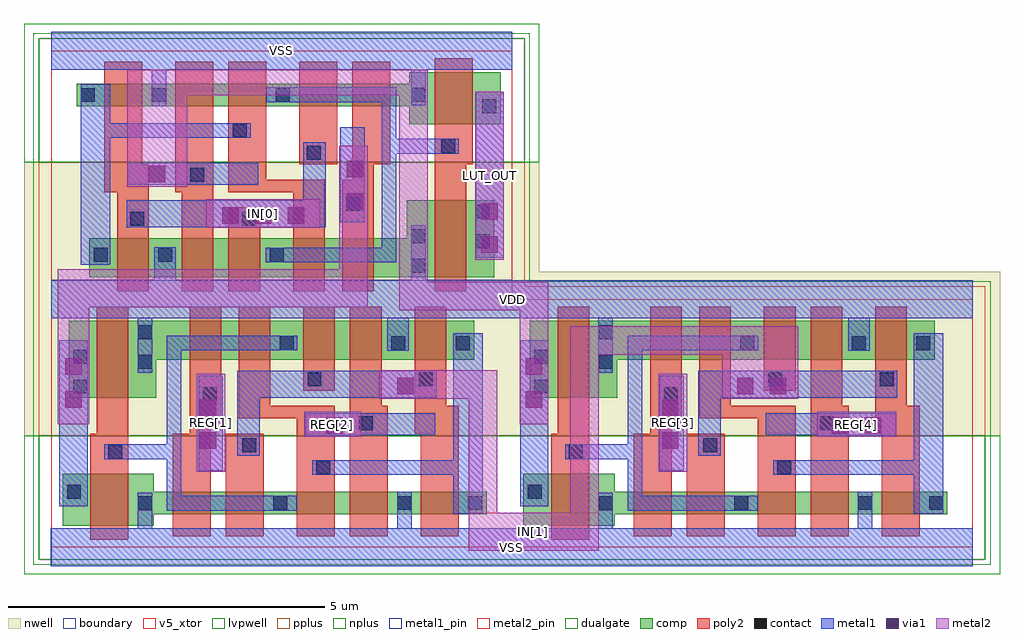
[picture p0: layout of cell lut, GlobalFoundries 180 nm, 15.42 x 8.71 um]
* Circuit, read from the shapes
.subckt lut IN[0] IN[1] LUT_OUT REG[1] REG[2] REG[3] REG[4] VDD VSS
XM1 VSS n1 gf180mcu_fd_sc_mcu7t5v0__mux2_1_2/I1 VSUBS nfet_05v0 w=0.82u l=0.6u
XM2 VSS IN[0] n2 VSUBS nfet_05v0 w=0.36u l=0.6u
XM3 n3 REG[1] VSS VSUBS nfet_05v0 w=0.36u l=0.6u
XM4 n4 gf180mcu_fd_sc_mcu7t5v0__mux2_1_2/I0 VSS VSUBS nfet_05v0 w=0.36u l=0.6u
XM5 n1 IN[1] n3 VSUBS nfet_05v0 w=0.36u l=0.6u
XM6 n5 n2 n4 VSUBS nfet_05v0 w=0.36u l=0.6u
XM7 n6 n7 n1 VSUBS nfet_05v0 w=0.36u l=0.6u
XM8 n8 IN[0] n5 VSUBS nfet_05v0 w=0.36u l=0.6u
XM9 VSS REG[2] n6 VSUBS nfet_05v0 w=0.36u l=0.6u
XM10 VSS gf180mcu_fd_sc_mcu7t5v0__mux2_1_2/I1 n8 VSUBS nfet_05v0 w=0.36u l=0.6u
XM11 n7 IN[1] VSS VSUBS nfet_05v0 w=0.36u l=0.6u
XM12 LUT_OUT n5 VSS VSUBS nfet_05v0 w=0.82u l=0.6u
XM13 VSS n9 gf180mcu_fd_sc_mcu7t5v0__mux2_1_2/I0 VSUBS nfet_05v0 w=0.82u l=0.6u
XM14 n10 REG[3] VSS VSUBS nfet_05v0 w=0.36u l=0.6u
XM15 n9 IN[1] n10 VSUBS nfet_05v0 w=0.36u l=0.6u
XM16 n11 n12 n9 VSUBS nfet_05v0 w=0.36u l=0.6u
XM17 VSS REG[4] n11 VSUBS nfet_05v0 w=0.36u l=0.6u
XM18 n12 IN[1] VSS VSUBS nfet_05v0 w=0.36u l=0.6u
XM19 VDD n1 gf180mcu_fd_sc_mcu7t5v0__mux2_1_2/I1 gf180mcu_fd_sc_mcu7t5v0__mux2_1_0/VNW pfet_05v0 w=1.22u l=0.5u
XM20 VDD IN[0] n2 gf180mcu_fd_sc_mcu7t5v0__mux2_1_0/VNW pfet_05v0 w=0.615u l=0.5u
XM21 n13 gf180mcu_fd_sc_mcu7t5v0__mux2_1_2/I0 VDD gf180mcu_fd_sc_mcu7t5v0__mux2_1_0/VNW pfet_05v0 w=0.615u l=0.5u
XM22 n14 REG[1] VDD gf180mcu_fd_sc_mcu7t5v0__mux2_1_0/VNW pfet_05v0 w=0.615u l=0.5u
XM23 n5 IN[0] n13 gf180mcu_fd_sc_mcu7t5v0__mux2_1_0/VNW pfet_05v0 w=0.615u l=0.5u
XM24 n1 n7 n14 gf180mcu_fd_sc_mcu7t5v0__mux2_1_0/VNW pfet_05v0 w=0.615u l=0.5u
XM25 n15 n2 n5 gf180mcu_fd_sc_mcu7t5v0__mux2_1_0/VNW pfet_05v0 w=0.615u l=0.5u
XM26 n16 IN[1] n1 gf180mcu_fd_sc_mcu7t5v0__mux2_1_0/VNW pfet_05v0 w=0.615u l=0.5u
XM27 VDD gf180mcu_fd_sc_mcu7t5v0__mux2_1_2/I1 n15 gf180mcu_fd_sc_mcu7t5v0__mux2_1_0/VNW pfet_05v0 w=0.615u l=0.5u
XM28 VDD REG[2] n16 gf180mcu_fd_sc_mcu7t5v0__mux2_1_0/VNW pfet_05v0 w=0.615u l=0.5u
XM29 n7 IN[1] VDD gf180mcu_fd_sc_mcu7t5v0__mux2_1_0/VNW pfet_05v0 w=0.615u l=0.5u
XM30 LUT_OUT n5 VDD gf180mcu_fd_sc_mcu7t5v0__mux2_1_0/VNW pfet_05v0 w=1.22u l=0.5u
XM31 VDD n9 gf180mcu_fd_sc_mcu7t5v0__mux2_1_2/I0 gf180mcu_fd_sc_mcu7t5v0__mux2_1_0/VNW pfet_05v0 w=1.22u l=0.5u
XM32 n17 REG[3] VDD gf180mcu_fd_sc_mcu7t5v0__mux2_1_0/VNW pfet_05v0 w=0.615u l=0.5u
XM33 n9 n12 n17 gf180mcu_fd_sc_mcu7t5v0__mux2_1_0/VNW pfet_05v0 w=0.615u l=0.5u
XM34 n18 IN[1] n9 gf180mcu_fd_sc_mcu7t5v0__mux2_1_0/VNW pfet_05v0 w=0.615u l=0.5u
XM35 VDD REG[4] n18 gf180mcu_fd_sc_mcu7t5v0__mux2_1_0/VNW pfet_05v0 w=0.615u l=0.5u
XM36 n12 IN[1] VDD gf180mcu_fd_sc_mcu7t5v0__mux2_1_0/VNW pfet_05v0 w=0.615u l=0.5u
.ends

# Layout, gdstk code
from math import pi, radians
import gdstk
lib = gdstk.Library(unit=1e-6, precision=1e-09)
def R(c, l, rs):  # rectangles x0, y0, x1, y1
    for r in rs: c.add(gdstk.rectangle(r[:2], r[2:], *l))
def A(c, l, x, y, w, h, nx, ny, dx, dy):  # array of equal rectangles
    R(c, l, [(x+i*dx, y+j*dy, x+i*dx+w, y+j*dy+h) for i in range(nx) for j in range(ny)])
def P(c, l, *ps):  # polygons
    for p in ps: c.add(gdstk.Polygon(p, *l))
boundary = (0, 0)
nwell = (21, 0)
comp = (22, 0)
poly2 = (30, 0)
pplus = (31, 0)
nplus = (32, 0)
contact = (33, 0)
metal1 = (34, 0)
metal1_pin = (34, 10)
via1 = (35, 0)
metal2 = (36, 0)
metal2_pin = (36, 10)
dualgate = (55, 0)
v5_xtor = (112, 1)
lvpwell = (204, 0)

gf180mcu_fd_sc_mcu7t5v0_ = lib.new_cell('gf180mcu_fd_sc_mcu7t5v0__mux2_1')
R(gf180mcu_fd_sc_mcu7t5v0_, boundary, [(0,0,7.28,3.92)])
R(gf180mcu_fd_sc_mcu7t5v0_, nwell, [(-0.43,1.76,7.71,4.35)])
P(gf180mcu_fd_sc_mcu7t5v0_, comp, [(0.28,2.36),(0.28,3.58),(6.68,3.58),(6.68,2.965),(1.66,2.965),(1.66,2.36)],
  [(0.18,0.34),(0.18,1.16),(1.62,1.16),(1.62,0.88),(6.88,0.88),(6.88,0.52),(1.62,0.52),(1.62,0.34)])
R(gf180mcu_fd_sc_mcu7t5v0_, poly2, [(2.76,0.175,3.36,1.795), (3.98,2.475,4.48,3.8)])
P(gf180mcu_fd_sc_mcu7t5v0_, poly2, [(0.62,0.12),(0.62,1.795),(0.72,1.795),(0.72,3.8),(1.22,3.8),(1.22,0.12)],
  [(1.92,0.175),(1.92,1.795),(2.185,1.795),(2.185,3.8),(2.685,3.8),(2.685,2.035),(2.52,2.035),(2.52,0.175)],
  [(3.88,0.175),(3.88,2.035),(2.96,2.035),(2.96,3.8),(3.46,3.8),(3.46,2.235),(4.48,2.235),(4.48,0.175)],
  [(4.72,0.175),(4.72,3.8),(5.22,3.8),(5.22,2.235),(5.32,2.235),(5.32,0.175)],
  [(5.84,0.175),(5.84,1.795),(5.74,1.795),(5.74,3.8),(6.24,3.8),(6.24,2.235),(6.44,2.235),(6.44,0.175)])
R(gf180mcu_fd_sc_mcu7t5v0_, pplus, [(-0.2,1.76,7.48,4.12)])
R(gf180mcu_fd_sc_mcu7t5v0_, nplus, [(-0.2,-0.2,7.48,1.76)])
R(gf180mcu_fd_sc_mcu7t5v0_, contact, [(1.37,0.585,1.59,0.805), (3.51,0.59,3.73,0.81), (5.47,0.59,5.69,0.81), (6.59,0.59,6.81,0.81), (0.25,0.765,0.47,0.985), (4.19,1.15,4.41,1.37), (0.9,1.4,1.12,1.62), (3.02,1.505,3.24,1.725), (4.86,1.85,5.08,2.07), (2.395,2.305,2.615,2.525), (0.35,2.43,0.57,2.65), (4.05,2.545,4.27,2.765), (5.81,2.545,6.03,2.765), (1.37,2.82,1.59,3.04), (0.35,2.9,0.57,3.12), (3.61,3.115,3.83,3.335), (5.37,3.115,5.59,3.335), (6.39,3.115,6.61,3.335), (1.37,3.29,1.59,3.51)])
R(gf180mcu_fd_sc_mcu7t5v0_, metal1, [(0.13,0.65,0.575,3.27), (2.33,1.21,2.71,2.71), (4.01,1.77,6.07,2.12)])
P(gf180mcu_fd_sc_mcu7t5v0_, metal1, [(1.825,0.575),(1.825,1.39),(0.84,1.39),(0.84,1.625),(1.825,1.625),(1.825,3.34),(3.89,3.34),(3.89,3.11),(2.055,3.11),(2.055,0.815),(3.88,0.815),(3.88,0.575)],
  [(2.94,1.445),(2.94,2.785),(6.09,2.785),(6.09,2.36),(3.295,2.36),(3.295,1.445)],
  [(6.35,0.53),(6.35,1.145),(4.125,1.145),(4.125,1.375),(6.35,1.375),(6.35,3.38),(6.815,3.38),(6.815,0.53)],
  [(0,-0.3),(0,0.3),(1.365,0.3),(1.365,0.865),(1.595,0.865),(1.595,0.3),(5.465,0.3),(5.465,0.88),(5.695,0.88),(5.695,0.3),(7.28,0.3),(7.28,-0.3)],
  [(1.365,2.76),(1.365,3.62),(0,3.62),(0,4.22),(7.28,4.22),(7.28,3.62),(5.65,3.62),(5.65,3.105),(5.31,3.105),(5.31,3.62),(1.595,3.62),(1.595,2.76)])
R(gf180mcu_fd_sc_mcu7t5v0_, dualgate, [(-0.28,-0.28,7.56,4.2)])
R(gf180mcu_fd_sc_mcu7t5v0_, v5_xtor, [(0,0,7.28,3.92)])
R(gf180mcu_fd_sc_mcu7t5v0_, lvpwell, [(-0.43,-0.43,7.71,1.76)])
gf180mcu_fd_sc_mcu7t5v0_.add(gdstk.Label('S', (4.2,2.52), layer=34, texttype=10))
gf180mcu_fd_sc_mcu7t5v0_.add(gdstk.Label('VDD', (3.64,3.92), layer=34, texttype=10))
gf180mcu_fd_sc_mcu7t5v0_.add(gdstk.Label('VSS', (3.64,0), layer=34, texttype=10))
gf180mcu_fd_sc_mcu7t5v0_.add(gdstk.Label('Z', (0.28,1.96), layer=34, texttype=10))
gf180mcu_fd_sc_mcu7t5v0_.add(gdstk.Label('I0', (4.76,1.96), layer=34, texttype=10))
gf180mcu_fd_sc_mcu7t5v0_.add(gdstk.Label('I1', (2.52,1.96), layer=34, texttype=10))
gf180mcu_fd_sc_mcu7t5v0_.add(gdstk.Label('& Vendor GLOBALFOUNDRIES', (0,2), layer=63, texttype=63))
gf180mcu_fd_sc_mcu7t5v0_.add(gdstk.Label('& Product GF018hv5v_mcu_sc7', (0,1.5), layer=63, texttype=63))
gf180mcu_fd_sc_mcu7t5v0_.add(gdstk.Label('& Version 2015q2v1', (0,1), layer=63, texttype=63))
gf180mcu_fd_sc_mcu7t5v0_.add(gdstk.Label('& Metric 1.00', (0,0.5), layer=63, texttype=63))
gf180mcu_fd_sc_mcu7t5v0_.add(gdstk.Label('VNW', (0.345,3.92), layer=21, texttype=10))
gf180mcu_fd_sc_mcu7t5v0_.add(gdstk.Label('VPW', (0.34,-0.085), layer=204, texttype=10))

lut = lib.new_cell('lut')
R(lut, nwell, [(10.2,0.05,10.7,1.85), (5.55,0.45,5.74,0.8)])
R(lut, pplus, [(2.39,1.795,2.44,1.865), (3.4,1.795,3.905,1.865), (8.42,1.795,8.79,1.865), (2.39,1.865,8.79,2.09), (2.39,2.09,2.76,2.16), (7.275,2.09,7.78,2.16), (8.74,2.09,8.79,2.16)])
R(lut, nplus, [(8.99,-1.585,9.25,-0.905)])
R(lut, metal1, [(4.3,-0.6,4.56,0.6), (11.6,-0.6,11.86,0.6), (6.1,-0.15,6.75,0.11), (14.17,-0.15,15.185,0.11), (2.15,0.1,2.45,1.2), (9.4,0.1,9.75,1.2), (7.2,0.45,7.9,0.75), (12.7,0.45,13.65,0.75), (8.7,2.7,9.05,3.5), (4.5,3.15,6.1,3.45), (6.6,3.25,6.9,4.3), (3.3,3.8,3.95,4.1)])
R(lut, metal1_pin, [(1.945,-2.245,16.51,-1.645), (1.95,1.675,16.51,2.275)])
A(lut, via1, 4.65, 3.17, 0.26, 0.26, 3, 1, 0.52, 0)
R(lut, via1, [(4.3,-0.39,4.56,-0.13), (11.6,-0.39,11.86,-0.13), (6.295,-0.15,6.555,0.11), (14.285,-0.15,14.545,0.11), (14.805,-0.15,15.065,0.11), (4.3,0.13,4.56,0.39), (11.6,0.13,11.86,0.39), (2.17,0.26,2.43,0.52), (9.445,0.26,9.705,0.52), (7.42,0.47,7.68,0.73), (12.785,0.47,13.045,0.73), (13.305,0.47,13.565,0.73), (2.17,0.78,2.43,1.04), (9.445,0.78,9.705,1.04), (8.745,2.71,9.005,2.97), (8.745,3.23,9.005,3.49), (6.62,3.385,6.88,3.645), (3.495,3.82,3.755,4.08), (6.62,3.905,6.88,4.165)])
R(lut, metal2, [(8.55,-2,10.6,-1.4), (8.55,-1.4,9,0.4), (10.15,-1.4,10.6,1.1), (4.25,-0.75,4.7,0.8), (11.55,-0.75,12,0.8), (5.95,-0.2,6.85,0.2), (14.05,-0.2,15.3,0.2), (2.05,0,2.55,1.85), (9.35,0,9.8,1.8), (7.135,0.4,9,0.85), (12.55,0.4,13.75,1.1), (10.15,1.1,13.75,1.55), (7.45,1.8,9.8,2.25), (2.05,1.85,6.95,2.45), (7.45,2.25,7.9,5.2), (6.5,2.45,6.95,4.4), (8.65,2.6,9.1,5.25), (4.4,3.1,6.2,3.55), (3.15,3.75,4.1,5.2), (3.15,5.2,7.9,5.6)])
R(lut, metal2_pin, [(8.55,-2,10.6,-1.4), (4.25,-0.75,4.7,0.8), (11.55,-0.75,12,0.8), (5.95,-0.2,6.85,0.2), (14.05,-0.2,15.3,0.2), (8.65,2.6,9.1,5.25), (4.4,3.1,6.2,3.55)])
R(lut, dualgate, [(8.79,-1.825,9.17,-1.665), (9.07,-1.665,9.17,-0.825), (8.79,-0.825,9.17,-0.665), (8.87,0.78,9.27,1.875), (8.59,1.875,9.55,1.92), (8.91,1.92,9.55,2.035), (2.31,2.035,2.59,2.08), (8.91,2.035,9.19,2.08)])
lut.add(gdstk.Reference(gf180mcu_fd_sc_mcu7t5v0_, (9.23,-1.945)))
lut.add(gdstk.Reference(gf180mcu_fd_sc_mcu7t5v0_, (1.95,-1.945)))
lut.add(gdstk.Reference(gf180mcu_fd_sc_mcu7t5v0_, (9.23,5.9), rotation=pi))
lut.add(gdstk.Label('VSS', (5.59,5.9), layer=34, texttype=0))
lut.add(gdstk.Label('REG[4]', (14.675,0), layer=36, texttype=10))
lut.add(gdstk.Label('REG[3]', (11.775,0.025), layer=36, texttype=10))
lut.add(gdstk.Label('REG[2]', (6.4,0), layer=36, texttype=10))
lut.add(gdstk.Label('REG[1]', (4.475,0.025), layer=36, texttype=10))
lut.add(gdstk.Label('IN[1]', (9.575,-1.7), layer=36, texttype=10))
lut.add(gdstk.Label('IN[0]', (5.3,3.325), layer=36, texttype=10))
lut.add(gdstk.Label('LUT_OUT', (8.875,3.925), layer=36, texttype=10))
lut.add(gdstk.Label('VSS', (9.227,-1.945), layer=34, texttype=10))
lut.add(gdstk.Label('VDD', (9.23,1.975), layer=34, texttype=10))

lib.write_gds('lut.gds')
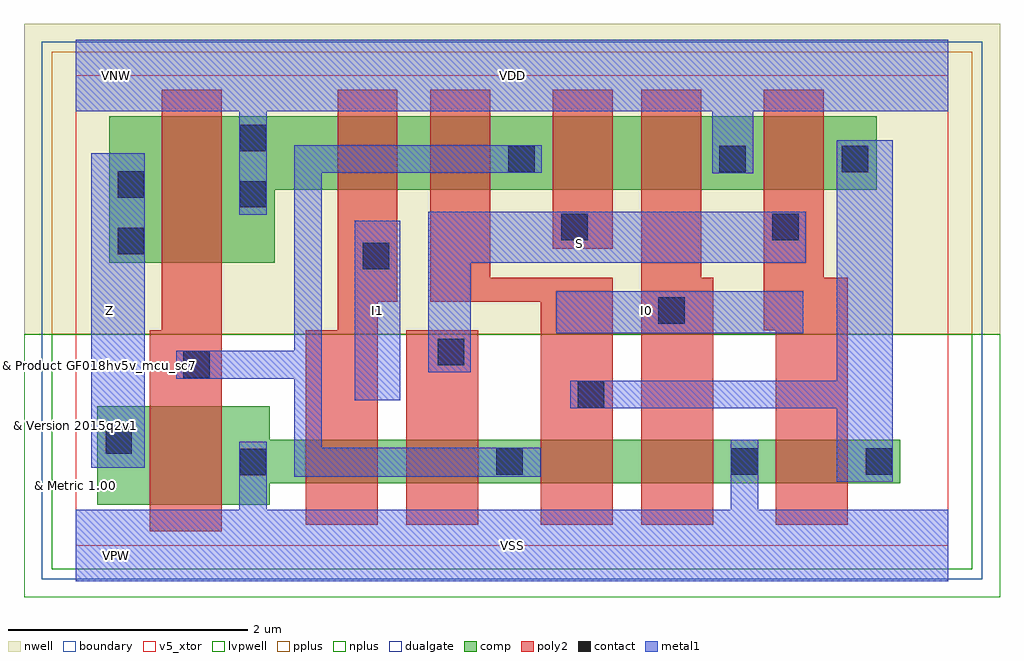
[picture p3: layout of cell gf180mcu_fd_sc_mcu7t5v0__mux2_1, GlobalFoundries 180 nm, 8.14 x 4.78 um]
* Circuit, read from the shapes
.subckt gf180mcu_fd_sc_mcu7t5v0__mux2_1 I0 I1 S VDD VNW VSS Z
XM1 VSS n1 Z VSUBS nfet_05v0 w=0.82u l=0.6u
XM2 n2 I1 VSS VSUBS nfet_05v0 w=0.36u l=0.6u
XM3 n1 S n2 VSUBS nfet_05v0 w=0.36u l=0.6u
XM4 n3 n4 n1 VSUBS nfet_05v0 w=0.36u l=0.6u
XM5 VSS I0 n3 VSUBS nfet_05v0 w=0.36u l=0.6u
XM6 n4 S VSS VSUBS nfet_05v0 w=0.36u l=0.6u
XM7 VDD n1 Z VNW pfet_05v0 w=1.22u l=0.5u
XM8 n5 I1 VDD VNW pfet_05v0 w=0.615u l=0.5u
XM9 n1 n4 n5 VNW pfet_05v0 w=0.615u l=0.5u
XM10 n6 S n1 VNW pfet_05v0 w=0.615u l=0.5u
XM11 VDD I0 n6 VNW pfet_05v0 w=0.615u l=0.5u
XM12 n4 S VDD VNW pfet_05v0 w=0.615u l=0.5u
.ends

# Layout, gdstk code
import gdstk
lib = gdstk.Library(unit=1e-6, precision=1e-09)
def R(c, l, rs):  # rectangles x0, y0, x1, y1
    for r in rs: c.add(gdstk.rectangle(r[:2], r[2:], *l))
def P(c, l, *ps):  # polygons
    for p in ps: c.add(gdstk.Polygon(p, *l))
boundary = (0, 0)
nwell = (21, 0)
comp = (22, 0)
poly2 = (30, 0)
pplus = (31, 0)
nplus = (32, 0)
contact = (33, 0)
metal1 = (34, 0)
dualgate = (55, 0)
v5_xtor = (112, 1)
lvpwell = (204, 0)

gf180mcu_fd_sc_mcu7t5v0_ = lib.new_cell('gf180mcu_fd_sc_mcu7t5v0__mux2_1')
R(gf180mcu_fd_sc_mcu7t5v0_, boundary, [(0,0,7.28,3.92)])
R(gf180mcu_fd_sc_mcu7t5v0_, nwell, [(-0.43,1.76,7.71,4.35)])
P(gf180mcu_fd_sc_mcu7t5v0_, comp, [(0.28,2.36),(0.28,3.58),(6.68,3.58),(6.68,2.965),(1.66,2.965),(1.66,2.36)],
  [(0.18,0.34),(0.18,1.16),(1.62,1.16),(1.62,0.88),(6.88,0.88),(6.88,0.52),(1.62,0.52),(1.62,0.34)])
R(gf180mcu_fd_sc_mcu7t5v0_, poly2, [(2.76,0.175,3.36,1.795), (3.98,2.475,4.48,3.8)])
P(gf180mcu_fd_sc_mcu7t5v0_, poly2, [(0.62,0.12),(0.62,1.795),(0.72,1.795),(0.72,3.8),(1.22,3.8),(1.22,0.12)],
  [(1.92,0.175),(1.92,1.795),(2.185,1.795),(2.185,3.8),(2.685,3.8),(2.685,2.035),(2.52,2.035),(2.52,0.175)],
  [(3.88,0.175),(3.88,2.035),(2.96,2.035),(2.96,3.8),(3.46,3.8),(3.46,2.235),(4.48,2.235),(4.48,0.175)],
  [(4.72,0.175),(4.72,3.8),(5.22,3.8),(5.22,2.235),(5.32,2.235),(5.32,0.175)],
  [(5.84,0.175),(5.84,1.795),(5.74,1.795),(5.74,3.8),(6.24,3.8),(6.24,2.235),(6.44,2.235),(6.44,0.175)])
R(gf180mcu_fd_sc_mcu7t5v0_, pplus, [(-0.2,1.76,7.48,4.12)])
R(gf180mcu_fd_sc_mcu7t5v0_, nplus, [(-0.2,-0.2,7.48,1.76)])
R(gf180mcu_fd_sc_mcu7t5v0_, contact, [(1.37,0.585,1.59,0.805), (3.51,0.59,3.73,0.81), (5.47,0.59,5.69,0.81), (6.59,0.59,6.81,0.81), (0.25,0.765,0.47,0.985), (4.19,1.15,4.41,1.37), (0.9,1.4,1.12,1.62), (3.02,1.505,3.24,1.725), (4.86,1.85,5.08,2.07), (2.395,2.305,2.615,2.525), (0.35,2.43,0.57,2.65), (4.05,2.545,4.27,2.765), (5.81,2.545,6.03,2.765), (1.37,2.82,1.59,3.04), (0.35,2.9,0.57,3.12), (3.61,3.115,3.83,3.335), (5.37,3.115,5.59,3.335), (6.39,3.115,6.61,3.335), (1.37,3.29,1.59,3.51)])
R(gf180mcu_fd_sc_mcu7t5v0_, metal1, [(0.13,0.65,0.575,3.27), (2.33,1.21,2.71,2.71), (4.01,1.77,6.07,2.12)])
P(gf180mcu_fd_sc_mcu7t5v0_, metal1, [(1.825,0.575),(1.825,1.39),(0.84,1.39),(0.84,1.625),(1.825,1.625),(1.825,3.34),(3.89,3.34),(3.89,3.11),(2.055,3.11),(2.055,0.815),(3.88,0.815),(3.88,0.575)],
  [(2.94,1.445),(2.94,2.785),(6.09,2.785),(6.09,2.36),(3.295,2.36),(3.295,1.445)],
  [(6.35,0.53),(6.35,1.145),(4.125,1.145),(4.125,1.375),(6.35,1.375),(6.35,3.38),(6.815,3.38),(6.815,0.53)],
  [(0,-0.3),(0,0.3),(1.365,0.3),(1.365,0.865),(1.595,0.865),(1.595,0.3),(5.465,0.3),(5.465,0.88),(5.695,0.88),(5.695,0.3),(7.28,0.3),(7.28,-0.3)],
  [(1.365,2.76),(1.365,3.62),(0,3.62),(0,4.22),(7.28,4.22),(7.28,3.62),(5.65,3.62),(5.65,3.105),(5.31,3.105),(5.31,3.62),(1.595,3.62),(1.595,2.76)])
R(gf180mcu_fd_sc_mcu7t5v0_, dualgate, [(-0.28,-0.28,7.56,4.2)])
R(gf180mcu_fd_sc_mcu7t5v0_, v5_xtor, [(0,0,7.28,3.92)])
R(gf180mcu_fd_sc_mcu7t5v0_, lvpwell, [(-0.43,-0.43,7.71,1.76)])
gf180mcu_fd_sc_mcu7t5v0_.add(gdstk.Label('S', (4.2,2.52), layer=34, texttype=10))
gf180mcu_fd_sc_mcu7t5v0_.add(gdstk.Label('VDD', (3.64,3.92), layer=34, texttype=10))
gf180mcu_fd_sc_mcu7t5v0_.add(gdstk.Label('VSS', (3.64,0), layer=34, texttype=10))
gf180mcu_fd_sc_mcu7t5v0_.add(gdstk.Label('Z', (0.28,1.96), layer=34, texttype=10))
gf180mcu_fd_sc_mcu7t5v0_.add(gdstk.Label('I0', (4.76,1.96), layer=34, texttype=10))
gf180mcu_fd_sc_mcu7t5v0_.add(gdstk.Label('I1', (2.52,1.96), layer=34, texttype=10))
gf180mcu_fd_sc_mcu7t5v0_.add(gdstk.Label('& Vendor GLOBALFOUNDRIES', (0,2), layer=63, texttype=63))
gf180mcu_fd_sc_mcu7t5v0_.add(gdstk.Label('& Product GF018hv5v_mcu_sc7', (0,1.5), layer=63, texttype=63))
gf180mcu_fd_sc_mcu7t5v0_.add(gdstk.Label('& Version 2015q2v1', (0,1), layer=63, texttype=63))
gf180mcu_fd_sc_mcu7t5v0_.add(gdstk.Label('& Metric 1.00', (0,0.5), layer=63, texttype=63))
gf180mcu_fd_sc_mcu7t5v0_.add(gdstk.Label('VNW', (0.345,3.92), layer=21, texttype=10))
gf180mcu_fd_sc_mcu7t5v0_.add(gdstk.Label('VPW', (0.34,-0.085), layer=204, texttype=10))

lib.write_gds('gf180mcu_fd_sc_mcu7t5v0__mux2_1.gds')
